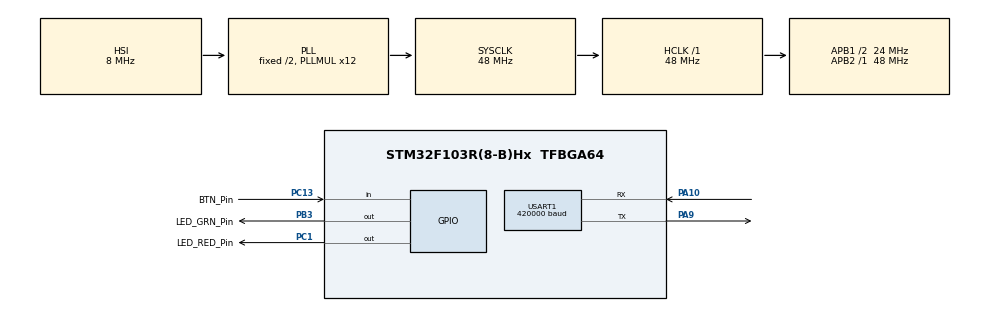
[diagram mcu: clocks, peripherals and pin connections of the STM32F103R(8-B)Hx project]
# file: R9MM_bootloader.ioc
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Mcu.Family=STM32F1
Mcu.Name=STM32F103R(8-B)Hx
Mcu.Package=TFBGA64
NVIC.PriorityGroup=NVIC_PRIORITYGROUP_4
PA10.Mode=Asynchronous
PA10.Signal=USART1_RX
PA13.Mode=Serial_Wire
PA13.Signal=SYS_JTMS-SWDIO
PA14.Mode=Serial_Wire
PA14.Signal=SYS_JTCK-SWCLK
PA9.Mode=Asynchronous
PA9.Signal=USART1_TX
PB3.GPIO_Label=LED_GRN_Pin
PB3.Signal=GPIO_Output
PC1.GPIO_Label=LED_RED_Pin
PC1.Signal=GPIO_Output
PC13-TAMPER-RTC.GPIO_Label=BTN_Pin
PC13-TAMPER-RTC.Signal=GPIO_Input
PD0-OSC_IN.Mode=HSE-External-Oscillator
PD0-OSC_IN.Signal=RCC_OSC_IN
PD1-OSC_OUT.Mode=HSE-External-Oscillator
PD1-OSC_OUT.Signal=RCC_OSC_OUT
ProjectManager.HeapSize=0x200
ProjectManager.StackSize=0x400
ProjectManager.TargetToolchain=TrueSTUDIO
RCC.AHBFreq_Value=48000000
RCC.APB1CLKDivider=RCC_HCLK_DIV2
RCC.APB1Freq_Value=24000000
RCC.APB1TimFreq_Value=48000000
RCC.APB2Freq_Value=48000000
RCC.APB2TimFreq_Value=48000000
RCC.HCLKFreq_Value=48000000
RCC.PLLMUL=RCC_PLL_MUL12
RCC.SYSCLKFreq_VALUE=48000000
RCC.SYSCLKSource=RCC_SYSCLKSOURCE_PLLCLK
RCC.USBFreq_Value=48000000
USART1.BaudRate=420000
USART1.VirtualMode=VM_ASYNC
board=custom

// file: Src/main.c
/* USER CODE BEGIN Header */
/**
  ******************************************************************************
  * @file           : main.c
  * @brief          : Main program body
  ******************************************************************************
  * @attention
  *
  * <h2><center>&copy; Copyright (c) 2020 STMicroelectronics.
  * All rights reserved.</center></h2>
  *
  * This software component is licensed by ST under BSD 3-Clause license,
  * the "License"; You may not use this file except in compliance with the
  * License. You may obtain a copy of the License at:
  *                        opensource.org/licenses/BSD-3-Clause
  *
  ******************************************************************************
  */
/* USER CODE END Header */

#include <string.h>
#include "main.h"

/* USER CODE BEGIN Includes */
#include "xmodem.h"
#include "flash.h"
/* USER CODE END Includes */

UART_HandleTypeDef huart1;

void SystemClock_Config(void);
static void MX_GPIO_Init(void);
static void MX_USART1_UART_Init(void);
/* USER CODE BEGIN PFP */
/*static void delay(int x) {
    for (int i = 0; i < x; i++)
        for (int j = 0; j < 500; j++)
            __asm__("nop");
}
*/
/* USER CODE END PFP */

int main(void)
{
  /* USER CODE BEGIN 1 */
  int i, ctr;
  /* USER CODE END 1 */

  /* MCU Configuration--------------------------------------------------------*/

  /* Reset of all peripherals, Initializes the Flash interface and the Systick. */
  HAL_Init();

  /* Configure the system clock */
  SystemClock_Config();

  /* Initialize all configured peripherals */
  MX_GPIO_Init();
  MX_USART1_UART_Init();
  /* USER CODE BEGIN 2 */
  HAL_GPIO_WritePin(LED_RED_GPIO_Port, LED_RED_Pin, 0);
  HAL_GPIO_WritePin(LED_GRN_GPIO_Port, LED_GRN_Pin, 1);
  /* Send welcome message on startup. */
  uart_transmit_str((uint8_t*)"\n\r==========================================\n\r");
  uart_transmit_str((uint8_t*)"UART Bootloader for ExpressLRS R9mm\n\r");
  uart_transmit_str((uint8_t*)"https://github.com/AlessandroAU/ExpressLRS\n\r");
  uart_transmit_str((uint8_t*)"==========================================\n\r\n\r");

  /* If the button is pressed, then jump to the user application,
   * otherwise stay in the bootloader. */
  uart_transmit_str((uint8_t*)"Send '2bl', 'bbb' or hold down button to begin bootloader\n\r");

  HAL_GPIO_WritePin(LED_RED_GPIO_Port, LED_RED_Pin, 1);
  HAL_GPIO_WritePin(LED_GRN_GPIO_Port, LED_GRN_Pin, 0);
  HAL_Delay(100);
  HAL_GPIO_WritePin(LED_RED_GPIO_Port, LED_RED_Pin, 1);
  HAL_GPIO_WritePin(LED_GRN_GPIO_Port, LED_GRN_Pin, 1);

  uint8_t header[6] = {0,0,0,0,0,0};

    uart_receive(header, 5u);

    bool BLrequested = false;
    /* Search for magic strings */
    if (strstr((char *)header, "2bl") || strstr((char *)header, "bbb")) {
    	BLrequested = true;
    }

    /* Read button a few times to make sure we pressed it and we are not sampling noise */
    ctr = 0;
    for (i=0;i<16;i++) {
    	/* Button is active low */
    	if (HAL_GPIO_ReadPin(BTN_GPIO_Port, BTN_Pin)==GPIO_PIN_RESET)
    		ctr++;
    	HAL_Delay(10);
    }
    /* if >75% of our samples is 'pressed', we assume it indeed was */
    if(ctr > 12)
    {
  	  uart_transmit_str((uint8_t*)"Detected button press\n\r");
  	  BLrequested = true;
    }

    if (BLrequested==true) {
    	/* BL was requested, GRN led on */
    	HAL_GPIO_WritePin(LED_RED_GPIO_Port, LED_RED_Pin, 0);
    	HAL_GPIO_WritePin(LED_GRN_GPIO_Port, LED_GRN_Pin, 1);
    } else {
    	/* BL was not requested, RED led on. Use app will soon use the LED's for it's own purpose,
    	 * thus if RED stays on there is an error */
    	HAL_GPIO_WritePin(LED_RED_GPIO_Port, LED_RED_Pin, 1);
    	HAL_GPIO_WritePin(LED_GRN_GPIO_Port, LED_GRN_Pin, 0);
    	uart_transmit_str((uint8_t*)"Jumping to user application...\n\r");
    	flash_jump_to_app();
    }

  /* USER CODE END 2 */

  /* Infinite loop */
  while (1)
  {

    /* USER CODE BEGIN 3 */
	  /* Turn on the green LED to indicate, that we are in bootloader mode.*/
	      //HAL_GPIO_WritePin(LED_RED_GPIO_Port, LED_RED_Pin, GPIO_PIN_SET);
	      /* Ask for new data and start the Xmodem protocol. */
	      //uart_transmit_str((uint8_t*)"Please send a new binary file with Xmodem protocol to update the firmware.\n\r");
	      xmodem_receive();
	      /* We only exit the xmodem protocol, if there are any errors.
	       * In that case, notify the user and start over. */
	      uart_transmit_str((uint8_t*)"\n\rFailed... Please try again.\n\r");
  }
  /* USER CODE END 3 */
}

void SystemClock_Config(void)
{
  RCC_OscInitTypeDef RCC_OscInitStruct = {0};
  RCC_ClkInitTypeDef RCC_ClkInitStruct = {0};

  /** Initializes the CPU, AHB and APB busses clocks
  */
  RCC_OscInitStruct.OscillatorType = RCC_OSCILLATORTYPE_HSI;
  RCC_OscInitStruct.HSIState = RCC_HSI_ON;
  RCC_OscInitStruct.HSICalibrationValue = RCC_HSICALIBRATION_DEFAULT;
  RCC_OscInitStruct.PLL.PLLState = RCC_PLL_ON;
  RCC_OscInitStruct.PLL.PLLSource = RCC_PLLSOURCE_HSI_DIV2;
  RCC_OscInitStruct.PLL.PLLMUL = RCC_PLL_MUL12;
  if (HAL_RCC_OscConfig(&RCC_OscInitStruct) != HAL_OK)
  {
    Error_Handler();
  }
  /** Initializes the CPU, AHB and APB busses clocks
  */
  RCC_ClkInitStruct.ClockType = RCC_CLOCKTYPE_HCLK|RCC_CLOCKTYPE_SYSCLK
                              |RCC_CLOCKTYPE_PCLK1|RCC_CLOCKTYPE_PCLK2;
  RCC_ClkInitStruct.SYSCLKSource = RCC_SYSCLKSOURCE_PLLCLK;
  RCC_ClkInitStruct.AHBCLKDivider = RCC_SYSCLK_DIV1;
  RCC_ClkInitStruct.APB1CLKDivider = RCC_HCLK_DIV2;
  RCC_ClkInitStruct.APB2CLKDivider = RCC_HCLK_DIV1;

  if (HAL_RCC_ClockConfig(&RCC_ClkInitStruct, FLASH_LATENCY_2) != HAL_OK)
  {
    Error_Handler();
  }
}

static void MX_USART1_UART_Init(void)
{

  huart1.Instance = USART1;
  huart1.Init.BaudRate = 420000;
  huart1.Init.WordLength = UART_WORDLENGTH_8B;
  huart1.Init.StopBits = UART_STOPBITS_1;
  huart1.Init.Parity = UART_PARITY_NONE;
  huart1.Init.Mode = UART_MODE_TX_RX;
  huart1.Init.HwFlowCtl = UART_HWCONTROL_NONE;
  huart1.Init.OverSampling = UART_OVERSAMPLING_16;
  if (HAL_UART_Init(&huart1) != HAL_OK)
  {
    Error_Handler();
  }

}

static void MX_GPIO_Init(void)
{
  GPIO_InitTypeDef GPIO_InitStruct = {0};

  /* GPIO Ports Clock Enable */
  __HAL_RCC_GPIOC_CLK_ENABLE();
  __HAL_RCC_GPIOB_CLK_ENABLE();
  __HAL_RCC_GPIOA_CLK_ENABLE();
  __HAL_RCC_GPIOD_CLK_ENABLE();

  /*Configure GPIO pin Output Level */
  HAL_GPIO_WritePin(LED_GRN_GPIO_Port, LED_GRN_Pin, GPIO_PIN_RESET);

  /*Configure GPIO pin Output Level */
  HAL_GPIO_WritePin(LED_RED_GPIO_Port, LED_RED_Pin, GPIO_PIN_RESET);

  /*Configure GPIO pin : BTN_Pin */
  GPIO_InitStruct.Pin = BTN_Pin;
  GPIO_InitStruct.Mode = GPIO_MODE_INPUT;
  GPIO_InitStruct.Pull = GPIO_NOPULL;
  HAL_GPIO_Init(BTN_GPIO_Port, &GPIO_InitStruct);

  /*Configure GPIO pin : LED_GRN_Pin */
  GPIO_InitStruct.Pin = LED_GRN_Pin;
  GPIO_InitStruct.Mode = GPIO_MODE_OUTPUT_PP;
  GPIO_InitStruct.Pull = GPIO_NOPULL;
  GPIO_InitStruct.Speed = GPIO_SPEED_FREQ_LOW;
  HAL_GPIO_Init(LED_GRN_GPIO_Port, &GPIO_InitStruct);

  /*Configure GPIO pin : LED_RED_Pin */
  GPIO_InitStruct.Pin = LED_RED_Pin;
  GPIO_InitStruct.Mode = GPIO_MODE_OUTPUT_PP;
  GPIO_InitStruct.Pull = GPIO_NOPULL;
  GPIO_InitStruct.Speed = GPIO_SPEED_FREQ_LOW;
  HAL_GPIO_Init(LED_RED_GPIO_Port, &GPIO_InitStruct);

}

void Error_Handler(void)
{
}

/************************ (C) COPYRIGHT STMicroelectronics *****END OF FILE****/
